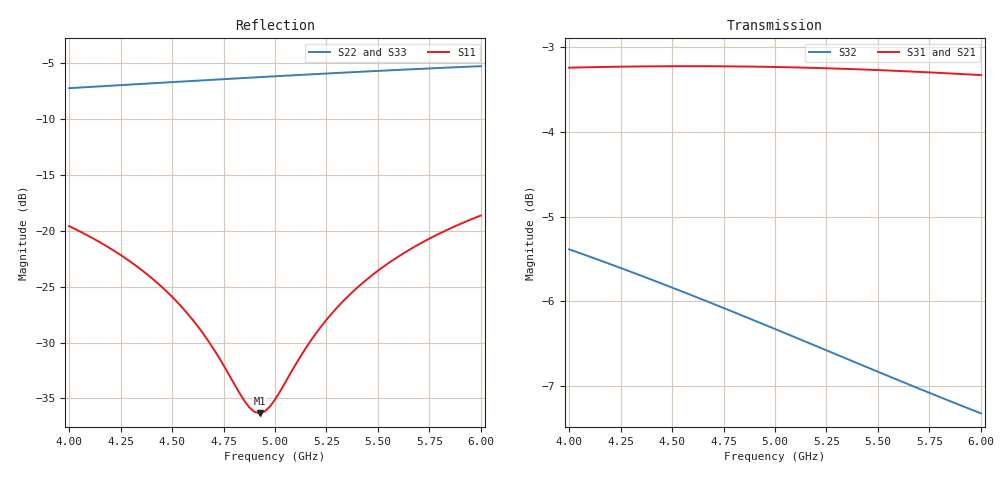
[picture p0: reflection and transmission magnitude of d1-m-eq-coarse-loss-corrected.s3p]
! yapnr Order 0 prediction d1-m-eq-coarse: predictions/D1/runs/d1-star/coarse_dense.s3p, loss-corrected
! substrate M-eq; coupon model OSHPARK-4L-FR408HR; correction: ratio (port line)
! |S21|, |S31| (and S12, S13) scaled, phases kept; 50 ohm, e^(+jwt)
# GHz S RI R 50
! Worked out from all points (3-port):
!   81 points, 4 GHz to 6 GHz, reference 50 ohm
!   strongest paths, dB at 4 GHz, 4.5 GHz, 5 GHz, 5.5 GHz, 6 GHz:
!     S31: -3.2, -3.2, -3.2, -3.3, -3.3
!     S21: -3.2, -3.2, -3.2, -3.3, -3.3
!     S32: -5.4, -5.8, -6.3, -6.8, -7.3
!   lowest |S11| = -36.3 dB at 4.925 GHz (marker M1), VSWR 1.03, Z = 48.5 + j0.223 ohm
!   |S11| at or under -10 dB: start of sweep to end of sweep
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4  -0.036 0.0986  -0.2257 -0.6504  -0.2257 -0.6504
   -0.2258 -0.6504  0.3198 0.295  -0.4024 -0.3569
   -0.2258 -0.6504  -0.4024 -0.3569  0.3198 0.295
4.5  -0.0157 0.0482  -0.3799 -0.5759  -0.3799 -0.5759
     -0.3799 -0.5759  0.4148 0.2057  -0.4612 -0.2193
     -0.3799 -0.5759  -0.4612 -0.2193  0.4148 0.2057
4.675  -0.0135 0.0293  -0.4287 -0.5405  -0.4287 -0.5405
       -0.4288 -0.5405  0.4424 0.1676  -0.471 -0.1707
       -0.4288 -0.5405  -0.471 -0.1707  0.4424 0.1676
4.85  -0.014 0.0103  -0.4742 -0.5008  -0.4742 -0.5008
      -0.4742 -0.5007  0.4663 0.1264  -0.4755 -0.1228
      -0.4742 -0.5007  -0.4755 -0.1228  0.4663 0.1264
4.925  -0.0151 0.0023  -0.4925 -0.4825  -0.4925 -0.4825
       -0.4925 -0.4824  0.4753 0.1079  -0.476 -0.1027
       -0.4925 -0.4824  -0.476 -0.1027  0.4753 0.1079
5  -0.0166 -0.00563  -0.51 -0.4635  -0.51 -0.4635
   -0.51 -0.4635  0.4836 0.089  -0.4756 -0.0829
   -0.51 -0.4635  -0.4756 -0.0829  0.4836 0.089
5.2  -0.0232 -0.026  -0.553 -0.4097  -0.553 -0.4097
     -0.553 -0.4097  0.5018 0.0365  -0.4706 -0.0318
     -0.553 -0.4097  -0.4706 -0.0318  0.5018 0.0365
5.4  -0.033 -0.0448  -0.5901 -0.3519  -0.5901 -0.3519
     -0.5901 -0.3519  0.514 -0.0182  -0.4605 0.0164
     -0.5901 -0.3519  -0.4605 0.0164  0.514 -0.0182
5.675  -0.0515 -0.0671  -0.6306 -0.2672  -0.6306 -0.2672
       -0.6306 -0.2671  0.5205 -0.0957  -0.4397 0.0773
       -0.6306 -0.2671  -0.4397 0.0773  0.5205 -0.0957
6  -0.0792 -0.0863  -0.6622 -0.1618  -0.6622 -0.1618
   -0.6621 -0.1618  0.5124 -0.188  -0.4069 0.1405
   -0.6621 -0.1618  -0.4069 0.1405  0.5124 -0.188
